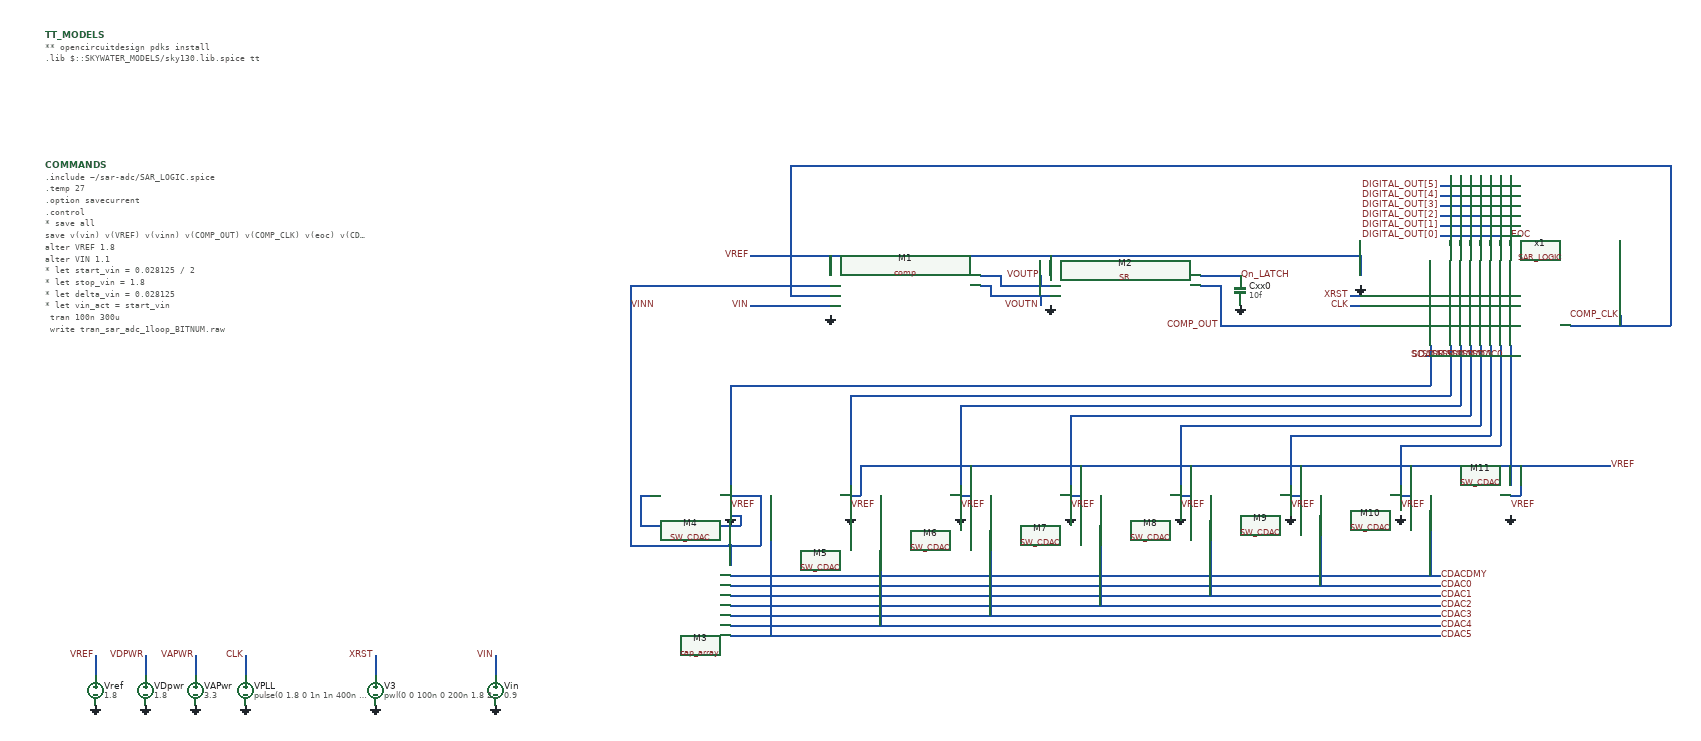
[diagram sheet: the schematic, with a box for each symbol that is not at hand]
v {xschem version=3.4.8RC file_version=1.3}
G {}
K {}
V {}
S {}
F {}
E {}
N 330 -310 330 -270 {
lab=VAPWR}
N 430 -310 430 -270 {
lab=CLK}
N 690 -310 690 -270 {
lab=XRST}
N 930 -310 930 -270 {
lab=VIN}
N 230 -310 230 -270 {
lab=VDPWR}
N 130 -310 130 -270 {
lab=VREF}
N 2380 -970 2660 -970 {
lab=COMP_OUT}
N 2640 -1010 2660 -1010 {
lab=CLK}
N 2640 -1030 2660 -1030 {
lab=XRST}
N 2960 -930 2960 -840 {
lab=SDAC0}
N 2950 -910 2960 -910 {
lab=SDAC0}
N 2940 -930 2940 -840 {
lab=SDAC1}
N 2930 -910 2940 -910 {
lab=SDAC1}
N 2920 -930 2920 -840 {
lab=SDAC2}
N 2910 -910 2920 -910 {
lab=SDAC2}
N 2900 -930 2900 -840 {
lab=SDAC3}
N 2890 -910 2900 -910 {
lab=SDAC3}
N 2880 -930 2880 -840 {
lab=SDAC4}
N 2870 -910 2880 -910 {
lab=SDAC4}
N 2860 -930 2860 -840 {
lab=SDAC5}
N 2850 -910 2860 -910 {
lab=SDAC5}
N 2840 -930 2840 -840 {
lab=SDAC6}
N 2830 -910 2840 -910 {
lab=SDAC6}
N 2800 -930 2800 -850 {
lab=SC}
N 2790 -910 2800 -910 {
lab=SC}
N 3080 -970 3280 -970 {
lab=COMP_CLK}
N 3180 -990 3180 -970 {
lab=COMP_CLK}
N 1900 -1070 1940 -1070 {
lab=VOUTP}
N 1900 -1050 1920 -1050 {
lab=VOUTN}
N 1400 -470 2820 -470 {
lab=CDACDMY}
N 1400 -450 2820 -450 {
lab=CDAC0}
N 1400 -430 2820 -430 {
lab=CDAC1}
N 1400 -410 2820 -410 {
lab=CDAC2}
N 1400 -390 2820 -390 {
lab=CDAC3}
N 1400 -370 2820 -370 {
lab=CDAC4}
N 1400 -350 2820 -350 {
lab=CDAC5}
N 1640 -830 2840 -830 {
lab=SDAC6}
N 1640 -830 1640 -650 {
lab=SDAC6}
N 1860 -810 1860 -650 {
lab=SDAC5}
N 1860 -810 2860 -810 {
lab=SDAC5}
N 2080 -790 2880 -790 {
lab=SDAC4}
N 2080 -790 2080 -650 {
lab=SDAC4}
N 2300 -770 2300 -650 {
lab=SDAC3}
N 2300 -770 2900 -770 {
lab=SDAC3}
N 2520 -750 2920 -750 {
lab=SDAC2}
N 2520 -750 2520 -650 {
lab=SDAC2}
N 2740 -730 2740 -650 {
lab=SDAC1}
N 2960 -840 2960 -650 {
lab=SDAC0}
N 1400 -850 2800 -850 {
lab=SC}
N 1400 -850 1400 -650 {
lab=SC}
N 1220 -630 1240 -630 {
lab=GND}
N 1220 -630 1220 -570 {
lab=GND}
N 1220 -570 1420 -570 {
lab=GND}
N 1420 -590 1420 -570 {
lab=GND}
N 1400 -590 1420 -590 {
lab=GND}
N 1400 -530 1400 -490 {
lab=VINN}
N 1200 -530 1400 -530 {
lab=VINN}
N 1200 -1050 1200 -530 {
lab=VINN}
N 1200 -1050 1600 -1050 {
lab=VINN}
N 1400 -630 1460 -630 {
lab=VINN}
N 1460 -630 1460 -530 {
lab=VINN}
N 1400 -530 1460 -530 {
lab=VINN}
N 2740 -730 2940 -730 {
lab=SDAC1}
N 1520 -1030 1600 -1030 {
lab=COMP_CLK}
N 1520 -1290 1520 -1030 {
lab=COMP_CLK}
N 1520 -1290 3280 -1290 {
lab=COMP_CLK}
N 3280 -1290 3280 -970 {
lab=COMP_CLK}
N 2340 -1050 2380 -1050 {
lab=COMP_OUT}
N 2380 -1050 2380 -970 {
lab=COMP_OUT}
N 2340 -1070 2420 -1070 {
lab=Qn_LATCH}
N 1660 -690 3160 -690 {
lab=VREF}
N 1640 -630 1660 -630 {
lab=VREF}
N 1660 -690 1660 -630 {
lab=VREF}
N 1860 -630 1880 -630 {
lab=VREF}
N 1880 -690 1880 -630 {
lab=VREF}
N 2080 -630 2100 -630 {
lab=VREF}
N 2100 -690 2100 -630 {
lab=VREF}
N 2300 -630 2320 -630 {
lab=VREF}
N 2320 -690 2320 -630 {
lab=VREF}
N 2520 -630 2540 -630 {
lab=VREF}
N 2540 -690 2540 -630 {
lab=VREF}
N 2740 -630 2760 -630 {
lab=VREF}
N 2760 -690 2760 -630 {
lab=VREF}
N 2960 -630 2980 -630 {
lab=VREF}
N 2980 -690 2980 -630 {
lab=VREF}
N 1440 -1010 1600 -1010 {
lab=VIN}
N 2020 -1030 2020 -1010 {
lab=VOUTN}
N 2020 -1070 2020 -1050 {
lab=VOUTP}
N 1940 -1070 1940 -1050 {
lab=VOUTP}
N 2840 -840 2840 -830 {
lab=SDAC6}
N 2860 -840 2860 -810 {
lab=SDAC5}
N 2880 -840 2880 -790 {
lab=SDAC4}
N 2900 -840 2900 -770 {
lab=SDAC3}
N 2920 -840 2920 -750 {
lab=SDAC2}
N 2940 -840 2940 -730 {
lab=SDAC1}
N 1920 -630 1920 -390 {
lab=CDAC3}
N 1700 -630 1700 -370 {
lab=CDAC4}
N 1480 -630 1480 -350 {
lab=CDAC5}
N 2840 -1270 2840 -1130 {
lab=DIGITAL_OUT[5]}
N 2820 -1250 2840 -1250 {
lab=DIGITAL_OUT[5]}
N 2820 -1230 2860 -1230 {
lab=DIGITAL_OUT[4]}
N 2820 -1210 2880 -1210 {
lab=DIGITAL_OUT[3]}
N 2820 -1190 2900 -1190 {
lab=DIGITAL_OUT[2]}
N 2820 -1170 2920 -1170 {
lab=DIGITAL_OUT[1]}
N 2820 -1150 2940 -1150 {
lab=DIGITAL_OUT[0]}
N 2860 -1270 2860 -1130 {
lab=DIGITAL_OUT[4]}
N 2880 -1270 2880 -1130 {
lab=DIGITAL_OUT[3]}
N 2900 -1270 2900 -1130 {
lab=DIGITAL_OUT[2]}
N 2920 -1270 2920 -1130 {
lab=DIGITAL_OUT[1]}
N 2940 -1270 2940 -1130 {
lab=DIGITAL_OUT[0]}
N 2960 -1270 2960 -1130 {
lab=EOC}
N 1920 -1050 1920 -1030 {
lab=VOUTN}
N 1920 -1030 2040 -1030 {
lab=VOUTN}
N 1940 -1050 2040 -1050 {
lab=VOUTP}
N 2140 -630 2140 -410 {lab=CDAC2}
N 2360 -630 2360 -430 {lab=CDAC1}
N 2580 -630 2580 -450 {lab=CDAC0}
N 2800 -630 2800 -470 {lab=CDACDMY}
N 1440 -1110 2660 -1110 {lab=VREF}
N 2660 -1110 2660 -1070 {lab=VREF}
N 2040 -1110 2040 -1070 {lab=VREF}
N 1600 -1110 1600 -1070 {lab=VREF}
C {devices/vsource.sym} 330 -240 0 0 {name=VAPwr value=3.3 savecurrent=false}
C {devices/gnd.sym} 430 -210 0 0 {name=l2 lab=GND}
C {devices/gnd.sym} 330 -210 0 0 {name=l3 lab=GND}
C {devices/simulator_commands_shown.sym} 30 -1290 0 0 {name=COMMANDS
simulator=ngspice
only_toplevel=false 
value=".include ~/sar-adc/SAR_LOGIC.spice
.temp 27
.option savecurrent
.control
* save all
save v(vin) v(VREF) v(vinn) v(COMP_OUT) v(COMP_CLK) v(eoc) v(CDACDMY) v(CDAC0) v(CDAC1) v(CDAC2) v(CDAC3) v(CDAC4) v(CDAC5) v(digital_out[5]) v(digital_out[4]) v(digital_out[3]) v(digital_out[2]) v(digital_out[1]) v(digital_out[0])

alter VREF 1.8
alter VIN  1.1

* let start_vin = 0.028125 / 2
* let stop_vin = 1.8
* let delta_vin = 0.028125
* let vin_act = start_vin

	tran 100n 300u
	write tran_sar_adc_1loop_BITNUM.raw
	meas tran vin FIND v(VIN) WHEN v(EOC)=0.9 FALL=LAST
	meas tran vinn FIND v(vinn) WHEN v(EOC)=0.9 FALL=LAST
	meas tran vout5 FIND v(DIGITAL_OUT[5]) WHEN v(EOC)=0.9 FALL=LAST
	meas tran vout4 FIND v(DIGITAL_OUT[4]) WHEN v(EOC)=0.9 FALL=LAST
	meas tran vout3 FIND v(DIGITAL_OUT[3]) WHEN v(EOC)=0.9 FALL=LAST
	meas tran vout2 FIND v(DIGITAL_OUT[2]) WHEN v(EOC)=0.9 FALL=LAST
	meas tran vout1 FIND v(DIGITAL_OUT[1]) WHEN v(EOC)=0.9 FALL=LAST
	meas tran vout0 FIND v(DIGITAL_OUT[0]) WHEN v(EOC)=0.9 FALL=LAST
	print vin >> tran_sar_adc_1loop_out_typ_BITNUM.txt
	print vout5 >> tran_sar_adc_1loop_out_typ_BITNUM.txt
	print vout4 >> tran_sar_adc_1loop_out_typ_BITNUM.txt
	print vout3 >> tran_sar_adc_1loop_out_typ_BITNUM.txt
	print vout2 >> tran_sar_adc_1loop_out_typ_BITNUM.txt
	print vout1 >> tran_sar_adc_1loop_out_typ_BITNUM.txt
	print vout0 >> tran_sar_adc_1loop_out_typ_BITNUM.txt

.endc
"}
C {devices/lab_pin.sym} 430 -310 0 0 {name=p2 sig_type=std_logic lab=CLK}
C {devices/lab_pin.sym} 690 -310 0 0 {name=p9 sig_type=std_logic lab=XRST}
C {devices/gnd.sym} 690 -210 0 0 {name=l1 lab=GND}
C {devices/lab_pin.sym} 930 -310 2 1 {name=p25 sig_type=std_logic lab=VIN}
C {devices/gnd.sym} 930 -210 0 0 {name=l22 lab=GND}
C {devices/vsource.sym} 930 -240 0 0 {name=Vin value=0.9 savecurrent=false}
C {devices/vsource.sym} 130 -240 0 0 {name=Vref value=1.8 savecurrent=false}
C {devices/gnd.sym} 130 -210 0 0 {name=l23 lab=GND}
C {devices/code.sym} 30 -1550 0 0 {name=TT_MODELS
only_toplevel=true
format="tcleval( @value )"
value="
** opencircuitdesign pdks install
.lib $::SKYWATER_MODELS/sky130.lib.spice tt
"
spice_ignore=false}
C {devices/lab_pin.sym} 330 -310 0 0 {name=p44 sig_type=std_logic lab=VAPWR}
C {devices/vsource.sym} 230 -240 0 0 {name=VDpwr value=1.8 savecurrent=false}
C {devices/gnd.sym} 230 -210 0 0 {name=l12 lab=GND
value=1.8}
C {devices/lab_pin.sym} 230 -310 0 0 {name=p45 sig_type=std_logic lab=VDPWR}
C {devices/lab_pin.sym} 130 -310 0 0 {name=p48 sig_type=std_logic lab=VREF}
C {devices/vsource.sym} 430 -240 0 0 {name=VPLL value="pulse(0 1.8 0 1n 1n 400n 800n)" savecurrent=false}
C {devices/vsource.sym} 690 -240 0 0 {name=V3 value="pwl(0 0 100n 0 200n 1.8 200n 1.8)" savecurrent=false}
C {devices/lab_pin.sym} 2640 -1010 0 0 {name=p5 sig_type=std_logic lab=CLK}
C {devices/lab_pin.sym} 2640 -1030 0 0 {name=p7 sig_type=std_logic lab=XRST}
C {devices/lab_pin.sym} 2950 -910 3 0 {name=p10 sig_type=std_logic lab=SDAC0}
C {devices/lab_pin.sym} 2930 -910 3 0 {name=p11 sig_type=std_logic lab=SDAC1}
C {devices/lab_pin.sym} 2910 -910 3 0 {name=p12 sig_type=std_logic lab=SDAC2}
C {devices/lab_pin.sym} 2890 -910 3 0 {name=p13 sig_type=std_logic lab=SDAC3}
C {devices/lab_pin.sym} 2870 -910 3 0 {name=p14 sig_type=std_logic lab=SDAC4}
C {devices/lab_pin.sym} 2850 -910 3 0 {name=p15 sig_type=std_logic lab=SDAC5}
C {devices/lab_pin.sym} 2830 -910 3 0 {name=p16 sig_type=std_logic lab=SDAC6}
C {devices/lab_pin.sym} 2790 -910 3 0 {name=p19 sig_type=std_logic lab=SC}
C {devices/lab_pin.sym} 3180 -990 0 0 {name=p20 sig_type=std_logic lab=COMP_CLK}
C {devices/gnd.sym} 1400 -590 0 1 {name=l4 lab=GND}
C {devices/gnd.sym} 1640 -590 0 1 {name=l5 lab=GND}
C {devices/gnd.sym} 1860 -590 0 1 {name=l6 lab=GND}
C {devices/gnd.sym} 2080 -590 0 1 {name=l7 lab=GND}
C {devices/gnd.sym} 2300 -590 0 1 {name=l8 lab=GND}
C {devices/gnd.sym} 2520 -590 0 1 {name=l9 lab=GND}
C {devices/gnd.sym} 2740 -590 0 1 {name=l10 lab=GND}
C {devices/gnd.sym} 2960 -590 0 1 {name=l11 lab=GND}
C {devices/gnd.sym} 2660 -1050 0 1 {name=l16 lab=GND}
C {devices/gnd.sym} 1600 -990 0 1 {name=l18 lab=GND}
C {devices/gnd.sym} 2040 -1010 0 1 {name=l19 lab=GND}
C {devices/capa.sym} 2420 -1040 0 0 {name=Cxx0
m=1
value=10f
footprint=1206
device="ceramic capacitor"}
C {devices/gnd.sym} 2420 -1010 0 1 {name=l20 lab=GND}
C {devices/lab_pin.sym} 1440 -1010 0 0 {name=p26 sig_type=std_logic lab=VIN}
C {devices/lab_pin.sym} 2020 -1010 0 0 {name=p27 sig_type=std_logic lab=VOUTN}
C {devices/lab_pin.sym} 2020 -1070 2 1 {name=p28 sig_type=std_logic lab=VOUTP}
C {devices/lab_pin.sym} 2820 -410 0 1 {name=p29 sig_type=std_logic lab=CDAC2}
C {devices/lab_pin.sym} 2820 -430 0 1 {name=p30 sig_type=std_logic lab=CDAC1}
C {devices/lab_pin.sym} 2820 -450 0 1 {name=p31 sig_type=std_logic lab=CDAC0}
C {devices/lab_pin.sym} 2820 -470 0 1 {name=p32 sig_type=std_logic lab=CDACDMY}
C {devices/lab_pin.sym} 2820 -390 0 1 {name=p33 sig_type=std_logic lab=CDAC3}
C {devices/lab_pin.sym} 2820 -370 0 1 {name=p34 sig_type=std_logic lab=CDAC4}
C {devices/lab_pin.sym} 2820 -350 0 1 {name=p35 sig_type=std_logic lab=CDAC5}
C {devices/lab_pin.sym} 1200 -1010 0 1 {name=p36 sig_type=std_logic lab=VINN}
C {devices/lab_pin.sym} 3160 -690 2 0 {name=p37 sig_type=std_logic lab=VREF}
C {devices/lab_pin.sym} 2420 -1070 2 0 {name=p38 sig_type=std_logic lab=Qn_LATCH}
C {devices/lab_pin.sym} 2380 -970 0 0 {name=p39 sig_type=std_logic lab=COMP_OUT}
C {devices/lab_pin.sym} 2820 -1250 0 0 {name=p18 sig_type=std_logic lab=DIGITAL_OUT[5]}
C {devices/lab_pin.sym} 2820 -1230 0 0 {name=p21 sig_type=std_logic lab=DIGITAL_OUT[4]}
C {devices/lab_pin.sym} 2820 -1210 0 0 {name=p40 sig_type=std_logic lab=DIGITAL_OUT[3]}
C {devices/lab_pin.sym} 2820 -1190 0 0 {name=p41 sig_type=std_logic lab=DIGITAL_OUT[2]}
C {devices/lab_pin.sym} 2820 -1170 0 0 {name=p42 sig_type=std_logic lab=DIGITAL_OUT[1]}
C {devices/lab_pin.sym} 2820 -1150 0 0 {name=p43 sig_type=std_logic lab=DIGITAL_OUT[0]}
C {devices/lab_pin.sym} 2960 -1150 2 0 {name=p17 sig_type=std_logic lab=EOC}
C {comp.sym} 1750 -1030 0 0 {name=M1
spiceprefix=X}
C {SR.sym} 2190 -1040 0 0 {name=M2
spiceprefix=X
}
C {SAR_LOGIC.sym} 2870 -1020 0 0 {name=x1 prefix=SAR_LOGIC}
C {cap_array.sym} 1250 -420 0 0 {name=M3
spiceprefix=X}
C {SW_CDAC.sym} 1400 -650 0 1 {name=M4
spiceprefix=X}
C {SW_CDAC.sym} 1640 -650 0 1 {name=M5
spiceprefix=X}
C {SW_CDAC.sym} 1860 -650 0 1 {name=M6
spiceprefix=X}
C {SW_CDAC.sym} 2080 -650 0 1 {name=M7
spiceprefix=X}
C {SW_CDAC.sym} 2300 -650 0 1 {name=M8
spiceprefix=X}
C {SW_CDAC.sym} 2520 -650 0 1 {name=M9
spiceprefix=X}
C {SW_CDAC.sym} 2740 -650 0 1 {name=M10
spiceprefix=X}
C {SW_CDAC.sym} 2960 -650 0 1 {name=M11
spiceprefix=X}
C {devices/lab_pin.sym} 1440 -1110 2 1 {name=p1 sig_type=std_logic lab=VREF}
C {devices/lab_pin.sym} 2960 -610 2 0 {name=p3 sig_type=std_logic lab=VREF}
C {devices/lab_pin.sym} 2740 -610 2 0 {name=p4 sig_type=std_logic lab=VREF}
C {devices/lab_pin.sym} 2520 -610 2 0 {name=p6 sig_type=std_logic lab=VREF}
C {devices/lab_pin.sym} 2300 -610 2 0 {name=p8 sig_type=std_logic lab=VREF}
C {devices/lab_pin.sym} 2080 -610 2 0 {name=p22 sig_type=std_logic lab=VREF}
C {devices/lab_pin.sym} 1860 -610 2 0 {name=p23 sig_type=std_logic lab=VREF}
C {devices/lab_pin.sym} 1640 -610 2 0 {name=p24 sig_type=std_logic lab=VREF}
C {devices/lab_pin.sym} 1400 -610 2 0 {name=p46 sig_type=std_logic lab=VREF}
